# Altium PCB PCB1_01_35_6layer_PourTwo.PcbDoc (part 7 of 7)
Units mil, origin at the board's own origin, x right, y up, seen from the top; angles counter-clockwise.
Board outline 1023.62 x 688.98 mil, 6 copper layers (Top Layer, Layer 1, Layer 2, Layer 3, Layer 4, Bottom Layer), stack 32.112 mil thick; 0 components, 1 nets, 8 pads, 81 vias.

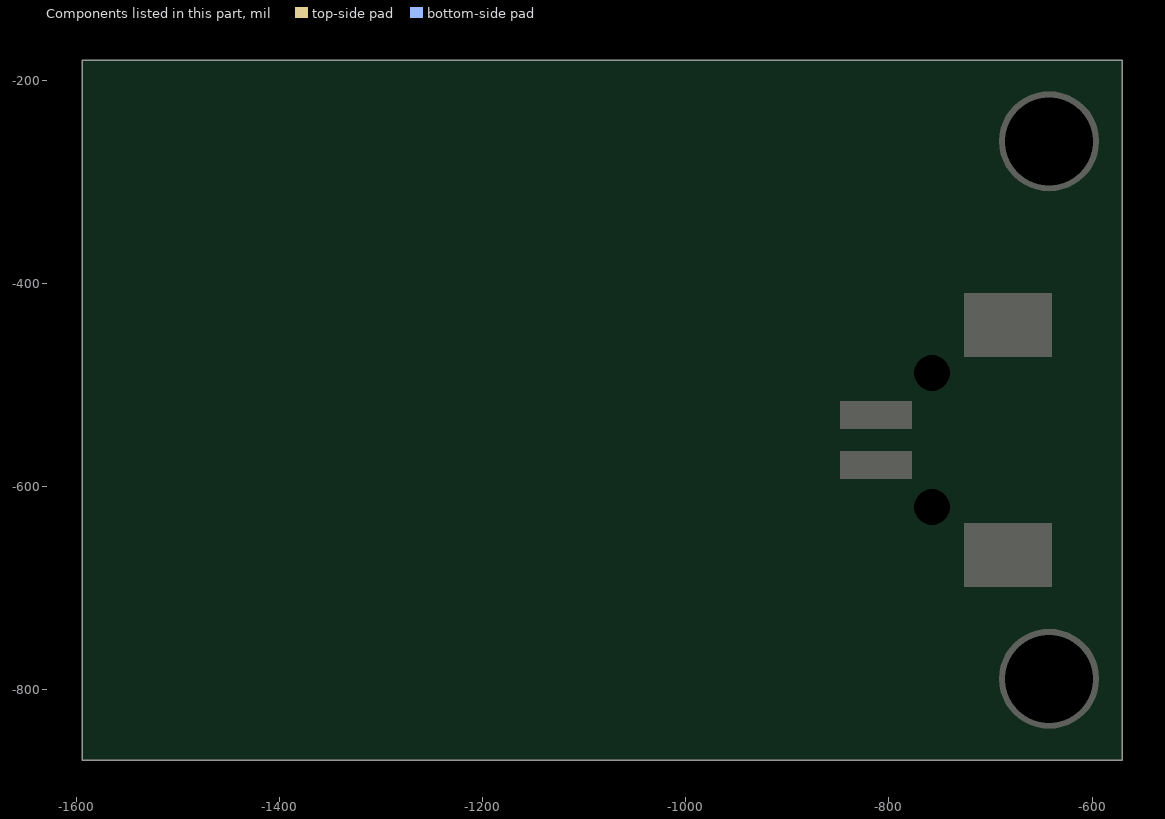
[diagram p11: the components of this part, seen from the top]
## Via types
v1: diameter 19.68, hole 11.81, Top Layer to Bottom Layer, tented both sides, 65 vias
v2: diameter 39.37, hole 19.68, Top Layer to Bottom Layer, 10 vias
v3: diameter 19.68, hole 11.81, Top Layer to Bottom Layer, 6 vias

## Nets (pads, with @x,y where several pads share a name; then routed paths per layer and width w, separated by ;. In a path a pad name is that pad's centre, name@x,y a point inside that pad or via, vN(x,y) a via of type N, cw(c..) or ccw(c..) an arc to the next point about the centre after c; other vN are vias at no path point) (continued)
copper on no net: (continued)
  Bottom Layer w3.94: -1461.98,-377.18 cw(c-1255.41,-519.9) -1425.28,-335.02 cw(c-1248.06,-527.67) -1380.34,-301.79 cw(c-1248.85,-525.96) -1329.45,-278.88 cw(c-1252.92,-513.07) -1274.85,-267.68 cw(c-1253.22,-516.36) -1219.21,-269.06 cw(c-1254.55,-527.16) -1165.21,-282.46 cw(c-1253.85,-525.77) -1115.33,-306.97 cw(c-1246.63,-514.62) -1072.08,-341.74 cw(c-1248.83,-515.94) -1037.83,-385.3 cw(c-1258.16,-521.9) -1013.84,-435.23 cw(c-1256.95,-521.66) -1001,-489.06 cw(c-1244,-520.15) -1000.21,-544.3 cw(c-1245.67,-519.37) -1011.89,-598.23 cw(c-1256.37,-515.91) -1034.98,-648.32 cw(c-1255.69,-516.53) -1068.13,-692.32 cw(c-1246.47,-525.36) -1110,-727.99 cw(c-1246.5,-524.21) -1158.78,-753.26 cw(c-1250.71,-513.6) -1211.86,-767.33 cw(c-1250.8,-514.2) -1266.66,-769.81 cw(c-1251.72,-526.67) -1320.59,-760.33 cw(c-1251.06,-526.64) -1370.93,-738.95 cw(c-1245.49,-516.49) -1415.41,-707.16 cw(c-1245.8,-516.56) -1452.09,-666.69 cw(c-1255.77,-523.64) -1479.04,-619.31 cw(c-1256.01,-524.43) -1494.6,-567.12 cw(c-1244.49,-522.22) -1498.42,-512.83 cw(c-1244.43,-522.04) -1490.65,-459.02 cw(c-1255.98,-518.94) -1471.41,-408.26 cw(c-1257.39,-518.91) -1441.26,-363.21 cw(c-1248.24,-526.48) -1402.03,-325.83 cw(c-1247.87,-526.66) -1355.82,-297.65 cw(c-1252.72,-516.03) -1304.68,-280.19 cw(c-1253.75,-514.2) -1250.98,-274.73 cw(c-1253.75,-526.23) -1197.42,-281.11 cw(c-1253.73,-526.92) -1146.48,-298.68 cw(c-1248.75,-516.66) -1100.64,-326.83 cw(c-1247.53,-514.14) -1062.37,-364.54 cw(c-1256.91,-521.89) -1033.28,-409.68 cw(c-1257.7,-522.48) -1014.44,-459.91 cw(c-1246.89,-519.85) -1006.93,-512.93 cw(c-1243.47,-519.18) -1011.57,-566.22 cw(c-1255.52,-516.87) -1027.74,-617.17 cw(c-1256.76,-516.51) -1054.32,-663.49 cw(c-1248.08,-523) -1090.23,-702.9 cw(c-1244.94,-525.75) -1134.04,-733.16 cw(c-1250.88,-514.89) -1183.38,-753.08 cw(c-1251.48,-513.42) -1235.78,-762.08 cw(c-1250.96,-523.97) -1288.79,-759.54 cw(c-1251.21,-528.8) -1339.81,-745.14 cw(c-1246.59,-517.21) -1386.39,-719.94 cw(c-1245.67,-515.57) -1426.53,-685.44 cw(c-1253.26,-522.5) -1458.23,-643.18 cw(c-1257.72,-525.7) -1479.56,-594.92 cw(c-1245.78,-521.86) -1489.78,-543.2 cw(c-1243.64,-521.5) -1488.79,-490.52 cw(c-1253.53,-520.1) -1476.48,-439.4 cw(c-1259.43,-518.46) -1453.01,-392.41 cw(c-1248.81,-525.24) -1419.82,-351.75 cw(c-1246.97,-526.87) -1378.78,-319.1 cw(c-1252.04,-518.6) -1331.76,-296.1 cw(c-1254.72,-512.42) -1280.83,-284.28 cw(c-1253.18,-524.96) -1228.6,-283.95 cw(c-1253.29,-527.7) -1177.51,-294.71 cw(c-1250.24,-518.79) -1130.04,-316.18 cw(c-1246.86,-512.3) -1088.65,-347.73 cw(c-1255.56,-521.49) -1055.26,-387.59 cw(c-1257.97,-523.3) -1031.12,-433.6 cw(c-1249.43,-520.09) -1017.46,-483.63 cw(c-1241.72,-518.49) -1015.39,-535.39 cw(c-1254.32,-517.64) -1024.78,-586.28 cw(c-1257.52,-516.86) -1044.75,-633.99 cw(c-1249.86,-521.25) -1074.45,-676.2 cw(c-1243.33,-526.56) -1112.84,-710.63 cw(c-1250.68,-516.32) -1157.82,-735.72 cw(c-1252.22,-513.11) -1207.09,-750.66 cw(c-1250.78,-521.53) -1258.31,-754.67 cw(c-1250.76,-530.44) -1309.06,-747.08 cw(c-1246.59,-515.82) -1399.55,-700.19 cw(c-1251.32,-521.1) -1435.12,-663.45 cw(c-1258.57,-527.06) -1461.51,-619.72 cw(c-1244.61,-520.96) -1482.93,-520.57 cw(c-1251.26,-520.66) -1477.32,-469.99 cw(c-1260.9,-518.75) -1460.54,-422 cw(c-1247.31,-525.64) -1398.09,-342.68 cw(c-1251.03,-520.65) -1355.74,-314.89 cw(c-1255.86,-511.62) -1308.3,-297.31 cw(c-1252.54,-526.47) -1207.86,-294.9 cw(c-1251.13,-520.85) -1159.68,-309.74 cw(c-1247.07,-511.04) -1116.1,-334.96 cw(c-1256.39,-523) -1050.54,-410.46 cw(c-1245.69,-518.31) -1023.05,-506.24 cw(c-1256.11,-517.94) -1039.36,-604.39 cw(c-1246.05,-523.06) -1095.37,-686.24 cw(c-1252.09,-515.05) -1180.98,-735.99 cw(c-1249.76,-525.69) -1279.27,-744.97 cw(c-1247.44,-516.34) -1371.71,-710.86 cw(c-1253.94,-524.56) -1440.95,-641.21 cw(c-1245.58,-520.66) -1473.43,-548.69 cw(c-1255.63,-520.82) -1463.95,-451.41 cw(c-1247.74,-524.7) -1413.6,-367.83 cw(c-1253.94,-517.34) -1333,-313.39 cw(c-1252.1,-525.51) -1236.98,-298.99 cw(c-1251.5,-522.7) -1188.99,-307.42 cw(c-1248.1,-511) -1144.12,-326.26 cw(c-1255.35,-522.69) -1072.19,-390.75 cw(c-1253.13,-521.62) -1048.21,-432.89 cw(c-1241.87,-516.76) -1034.19,-479.24 cw(c-1255.18,-518.53) -1038.02,-575.28 cw(c-1253.33,-519.47) -1055.12,-620.4 cw(c-1242.38,-525.07) -1081.75,-660.55 cw(c-1251.92,-516.16) -1157.82,-718.52 cw(c-1251.65,-517.82) -1203.26,-734.02 cw(c-1249,-529.85) -1250.93,-739.07 cw(c-1248.18,-517.21) -1343.62,-717.51 cw(c-1249.12,-518.12) -1384.31,-692.5 cw(c-1256.7,-527.8) -1418.43,-659.17 cw(c-1246.74,-520.67) -1460.67,-574.44 cw(c-1247.66,-520.41) -1467.3,-527.38 cw(c-1259.91,-520.74) -1463.39,-480.08 cw(c-1248.51,-523.81) -1425.22,-393.97 cw(c-1248.57,-523.16) -1393.34,-359.04 cw(c-1256.58,-513.97) -1354.61,-332.04 cw(c-1253.58,-520.23) -1310.87,-314.46 cw(c-1251.39,-527.55) -1264.39,-306.7 cw(c-1251.44,-524.25) -1217.4,-308.99 cw(c-1249.47,-512.32) -1172.14,-321.55 cw(c-1252.19,-518.09) -1130.93,-343.94 cw(c-1256.55,-524.58) -1095.51,-374.65 cw(c-1254.23,-522.64) -1067.47,-412.12 cw(c-1243.88,-516.61) -1048.39,-454.78 cw(c-1249.52,-518) -1039.41,-500.56 cw(c-1257.47,-518.79) -1040.5,-547.19 cw(c-1254.77,-519.3) -1051.45,-592.45 cw(c-1243.66,-523.4) -1072.05,-634.13 cw(c-1247.82,-520.23) -1101.45,-670.04 cw(c-1253.62,-514.49) -1137.88,-698.76 cw(c-1252.43,-516.66) -1179.52,-719.07 cw(c-1248.56,-527.69) -1224.52,-729.71 cw(c-1248.69,-523.06) -1270.69,-729.96 cw(c-1247.94,-514.77) -1315.81,-720.23 cw(c-1248.77,-516.8) -1357.77,-701.19 cw(c-1254.72,-526.67) -1394.48,-673.45 cw(c-1251.63,-524.07) -1423.94,-638.21 cw(c-1244.64,-519.28) -1445.09,-597.47 cw(c-1246.48,-519.84) -1457.09,-553.22 cw(c-1257.69,-521.51) -1459.11,-507.5 cw(c-1254.34,-522.21) -1450.79,-462.58 cw(c-1246.04,-524.6) -1432.96,-420.54 cw(c-1247.41,-523.66) -1406.65,-383.29 cw(c-1255.7,-516.21) -1372.9,-352.75 cw(c-1254.47,-518.75) -1333.19,-330.64 cw(c-1250.96,-526.8) -1289.66,-317.65 cw(c-1251.07,-525.42) -1244.43,-314.21 cw(c-1250.61,-514.48) -1199.62,-320.71 cw(c-1251.64,-516.45) -1157.5,-337.12 cw(c-1255.68,-524.4) -1119.95,-362.25 cw(c-1254.85,-523.64) -1088.64,-394.74 cw(c-1246.3,-517.16) -1065.21,-433.2 cw(c-1247.91,-517.35) -1051.08,-475.89 cw(c-1256.74,-519.34) -1046.54,-520.59 cw(c-1255.9,-519.49) -1051.59,-565.19 cw(c-1245.67,-521.89) -1066.2,-607.53 cw(c-1246.28,-521.04) -1089.96,-645.43 cw(c-1253.54,-515.41) -1121.35,-677.24 cw(c-1253.28,-515.96) -1158.73,-701.64 cw(c-1248.72,-525.18) -1200.44,-717.29 cw(c-1248.3,-524.75) -1244.54,-723.11 cw(c-1248.59,-515.45) -1288.82,-719.22 cw(c-1248.8,-515.75) -1331.22,-706.04 cw(c-1252.9,-524.92) -1369.66,-684 cw(c-1252.67,-525.47) -1402.08,-653.89 cw(c-1245.6,-519.24) -1427.16,-617.49 cw(c-1245.73,-519.15) -1443.93,-576.64 cw(c-1255.2,-521.77) -1451.41,-533.21 cw(c-1256.07,-522.32) -1448.91,-489.28 cw(c-1246.65,-523.83) -1436.9,-446.98 cw(c-1246.43,-523.76) -1416.22,-408.24 cw(c-1254.29,-518.27) -1387.69,-374.98 cw(c-1255.68,-517.5) -1352.44,-349.05 cw(c-1250.78,-525.81) -1312.42,-331.44 cw(c-1250.52,-526.18) -1269.62,-322.73 cw(c-1251.27,-516.86) -1226.04,-323.51 cw(c-1251.48,-514.72) -1183.83,-334.07 cw(c-1254.8,-523.88) -1144.97,-353.59 cw(c-1255.04,-524.53) -1111.17,-380.87 cw(c-1248.51,-518.17) -1084.14,-414.74 cw(c-1246.5,-516.35) -1065.47,-453.79 cw(c-1255.76,-519.66) -1055.8,-495.93 cw(c-1256.65,-519.91) -1055.28,-539.12 cw(c-1247.83,-520.87) -1064.11,-581.31 cw(c-1244.62,-521.45) -1082.19,-620.36 cw(c-1253.14,-516.39) -1108.35,-654.49 cw(c-1254.07,-515.69) -1141.12,-682.25 cw(c-1249.32,-522.91) -1179.03,-702.23 cw(c-1247.54,-526.26) -1220.42,-713.14 cw(c-1249.07,-516.41) -1263.14,-714.72 cw(c-1249.11,-515.01) -1305.18,-707.2 cw(c-1251.58,-523.04) -1344.52,-690.82 cw(c-1253.31,-527) -1379.11,-666.03 cw(c-1246.65,-519.51) -1407.4,-634.29 cw(c-1245.41,-518.45) -1428.28,-597.31 cw(c-1252.95,-521.57) -1440.66,-556.79 cw(c-1257.61,-522.84) -1443.6,-514.57 cw(c-1247.56,-523.19) -1437.21,-472.79 cw(c-1245.73,-523.54) -1422.1,-433.36 cw(c-1252.73,-519.82) -1398.91,-398.19 cw(c-1257.04,-516.71) -1368.43,-369.18 cw(c-1250.9,-524.7) -1332.37,-347.6 cw(c-1249.9,-526.54) -1292.59,-334.19 cw(c-1251.45,-519.01) -1250.94,-329.67 cw(c-1251.77,-513.23) -1209.4,-334.62 cw(c-1254.02,-523.06) -1170.02,-348.58 cw(c-1254.9,-525.19) -1134.54,-370.57 cw(c-1250.23,-519.4) -1104.68,-399.6 cw(c-1245.62,-515.2) -1082.14,-434.56 cw(c-1254.61,-519.72) -1067.88,-473.58 cw(c-1257.03,-520.45) -1062.24,-514.69 cw(c-1249.84,-520.36) -1065.57,-555.97 cw(c-1243.24,-521.35) -1078.06,-595.39 cw(c-1252.42,-517.3) -1098.91,-631.03 cw(c-1254.7,-515.78) -1126.84,-661.4 cw(c-1250.21,-521.09) -1160.56,-685.01 cw(c-1246.59,-527.16) -1198.67,-700.43 cw(c-1249.3,-517.56) -1239.19,-707.04 cw(c-1249.59,-514.62) -1280.15,-704.88 cw(c-1250.78,-521.23) -1319.61,-694.01 cw(c-1253.32,-528.23) -1355.57,-674.59 cw(c-1246.25,-518.44) -1410.6,-615 cw(c-1251.09,-521.03) -1427.27,-577.88 cw(c-1258.45,-523.61) -1435.2,-538.04 cw(c-1246.41,-522.84) -1424.41,-458.13 cw(c-1251.15,-520.87) -1406.55,-421.84 cw(c-1258.1,-516.65) -1381.05,-390.52 cw(c-1249.86,-525.43) -1313,-348.16 cw(c-1251.23,-520.85) -1273.89,-338.85 cw(c-1252.42,-512.5) -1233.75,-338.53 cw(c-1253.95,-524.39) -1158.2,-363.81 cw(c-1248.42,-516.68) -1100.6,-418.41 cw(c-1255.67,-520.64) -1072.11,-492.29 cw(c-1246.52,-520.05) -1077.42,-570.99 ; -1461.97,-377.18 ccw(c-1258.39,-517.16) -1488.26,-426.6 ccw(c-1245.64,-522.33) -1503.11,-480.66 ccw(c-1243.5,-522.86) -1506.15,-536.7 ccw(c-1253.98,-523.57) -1497.02,-592.09 ccw(c-1258.7,-524.33) -1475.61,-644.07 ccw(c-1246.41,-517.7) -1443.28,-690.16 ccw(c-1244.38,-516.17) -1401.86,-728.39 ccw(c-1250.39,-524.53) -1353.15,-756.79 ccw(c-1253.09,-529.34) -1299.22,-773.5 ccw(c-1250.33,-515.45) -1242.86,-777.99 ccw(c-1250.23,-512.58) -1186.76,-770.39 ccw(c-1247.66,-522.34) -1133.6,-750.88 ccw(c-1245.32,-528.12) -1086.14,-719.86 ccw(c-1254.39,-517.01) -1046.6,-679.11 ccw(c-1256.8,-514.9) -1016.57,-630.84 ccw(c-1247.84,-519.05) -997.64,-577.21 ccw(c-1241.19,-521.06) -991.25,-520.63 ccw(c-1255.68,-520.97) -997.48,-463.95 ccw(c-1259.18,-521.55) -1015.62,-409.81 ccw(c-1250.47,-517.38) -1045,-360.84 ccw(c-1244.14,-513.1) -1084.68,-319.67 ccw(c-1253.53,-524.32) -1132.52,-288.21 ccw(c-1255.47,-527.68) -1186.03,-267.6 ccw(c-1253.19,-518.53) -1242.73,-258.98 ccw(c-1252.46,-510.24) -1299.99,-263.33 ccw(c-1249.77,-524.73) -1354.95,-280.21 ccw(c-1248.28,-528.68) -1405.15,-308.43 ccw(c-1253.75,-521.28) -1448.11,-346.78 ccw(c-1260.18,-515.02) -1481.41,-393.87 ccw(c-1247.23,-522.21) -1503.52,-447.2 ccw(c-1246.64,-523) -1511.63,-561.9 ccw(c-1261.41,-524.29) -1496.53,-617.8 ccw(c-1247.57,-518.86) -1469.41,-669.05 ccw(c-1246.19,-518.63) -1385.85,-748.74 ccw(c-1254.84,-531.29) -1332.93,-772.84 ccw(c-1250.21,-517.14) -1275.92,-784.66 ccw(c-1249.48,-515.45) -1160.78,-771 ccw(c-1245.04,-530.62) -1108.25,-745.49 ccw(c-1252.99,-518.05) -1062.62,-708.94 ccw(c-1254.18,-516.08) -999.5,-611.11 ccw(c-1239.23,-522.43) -985.6,-554.14 ccw(c-1253.93,-520.57) -984.68,-495.45 ccw(c-1256.7,-520.3) -1019.99,-383.99 ccw(c-1241.94,-512.59) -1055.15,-336.77 ccw(c-1252.67,-522.68) -1099.98,-298.5 ccw(c-1254.91,-525.05) -1208.81,-254.49 ccw(c-1251.79,-515.44) -1326.15,-261.64 ccw(c-1249.92,-526.67) -1429.86,-317.69 ccw(c-1255.73,-517.79) -1499.43,-413.04 ccw(c-1245.41,-523.7) -1522.43,-529.15 ccw(c-1256.47,-522.59) -1493.19,-644 ccw(c-1244.89,-518.16) -1418.07,-736.1 ccw(c-1253.04,-526.42) -1310.52,-786.99 ccw(c-1248.98,-514.18) -1191.19,-787.81 ccw(c-1247.64,-526.19) -1082.98,-737.18 ccw(c-1254.8,-514.9) -1005.99,-645.38 ccw(c-1244.24,-521.67) -975.89,-529.27 ccw(c-1257.97,-519.99) -997.65,-410.96 ccw(c-1245.62,-515.92) -1068.2,-313.37 ccw(c-1255.95,-525.79) -1173.66,-254.5 ccw(c-1250.27,-508.3) -1233.51,-243.72 ccw(c-1250.8,-520.69) -1294.31,-246.61 ccw(c-1250.04,-527.91) -1407.33,-290.53 ccw(c-1259.95,-512.38) -1453.98,-329.92 ccw(c-1251.07,-520.33) -1490.65,-378.8 ccw(c-1244.57,-524.59) -1528.99,-494.35 ccw(c-1262.84,-522.36) -1528.38,-555.64 ccw(c-1251.59,-520.61) -1514.04,-615.28 ccw(c-1243.69,-518.13) -1449.18,-718.88 ccw(c-1257.01,-530.77) -1401.39,-757.64 ccw(c-1251.52,-521.45) -1346.07,-784.71 ccw(c-1247.93,-512.02) -1286.12,-799.31 ccw(c-1248.31,-516.41) -1224.42,-800.82 ccw(c-1246.96,-531.52) -1163.85,-788.66 ccw(c-1250.49,-521.94) -1107.51,-763.2 ccw(c-1255.65,-512.86) -1057.87,-726.16 ccw(c-1252.73,-515.72) -1017.22,-679.39 ccw(c-1240.19,-524.32) -987.85,-624.77 ccw(c-1249.24,-521.2) -971.5,-564.9 ccw(c-1259.86,-519.34) -968.39,-502.79 ccw(c-1256.13,-518.93) -978.56,-441.42 ccw(c-1241.5,-514.74) -1002.01,-383.75 ccw(c-1249.07,-519.44) -1037.85,-332.79 ccw(c-1257.52,-526.66) -1083.91,-290.65 ccw(c-1255.66,-523.79) -1137.89,-259.25 ccw(c-1249.58,-509.86) -1197.5,-240.47 ccw(c-1250.62,-518) -1259.86,-235.59 ccw(c-1250.43,-529.45) -1321.92,-244.26 ccw(c-1251.37,-526.53) -1380.75,-265.93 ccw(c-1258.22,-513.01) -1433.42,-300.01 ccw(c-1253.04,-518.41) -1477.11,-345.12 ccw(c-1243.84,-525.77) -1510.1,-398.67 ccw(c-1246.38,-524.78) -1530.98,-458.05 ccw(c-1261.1,-521.46) -1538.33,-520.6 ccw(c-1254.39,-520.88) -1531.4,-583.25 ccw(c-1242.53,-518.4) -1511.08,-643.03 ccw(c-1244.6,-519.59) -1478.51,-697.17 ccw(c-1256.45,-528.76) -1434.84,-742.89 ccw(c-1253.15,-523.81) -1381.94,-777.62 ccw(c-1247.35,-512.79) -1322.7,-800.14 ccw(c-1247.66,-514.8) -1259.98,-809.59 ccw(c-1248.14,-529.67) -1196.68,-805.07 ccw(c-1249.73,-524.76) -1135.97,-786.38 ccw(c-1254.66,-512.96) -1080.65,-754.96 ccw(c-1253.51,-514.2) -1033.21,-712.49 ccw(c-1242.46,-523.95) -996.2,-660.65 ccw(c-1246.55,-522.47) -971.8,-601.74 ccw(c-1259.09,-518.66) -960.71,-538.84 ccw(c-1257.77,-518.54) -963.22,-474.98 ccw(c-1243.35,-516.26) -979.63,-413.18 ccw(c-1246.31,-518.17) -1009.57,-356.62 ccw(c-1257.51,-525.59) -1051.13,-307.8 ccw(c-1257.01,-524.76) -1102.14,-268.89 ccw(c-1249.67,-512.33) -1160.43,-242.02 ccw(c-1249.79,-515.02) -1223.34,-228.99 ccw(c-1251.24,-528.7) -1287.68,-229.91 ccw(c-1251.52,-528.15) -1350.41,-244.47 ccw(c-1256.36,-514.74) -1408.48,-272.35 ccw(c-1254.82,-515.81) -1458.82,-312.66 ccw(c-1244.97,-525.87) -1499.27,-363.02 ccw(c-1245.27,-525.93) -1528.14,-420.86 ccw(c-1258.51,-521.18) -1543.73,-483.61 ccw(c-1257.58,-520.56) -1544.77,-548.33 ccw(c-1243.24,-519.35) -1531.7,-611.83 ccw(c-1243.02,-519.5) -1505.43,-671.16 ccw(c-1254.95,-526.58) -1466.88,-723.38 ccw(c-1255.49,-526.07) -1417.49,-765.59 ccw(c-1247.11,-513.99) -1360.01,-796.1 ccw(c-1246.72,-513.58) -1297.32,-813.73 ccw(c-1248.83,-527.08) -1232.27,-817.34 ccw(c-1249.51,-528.07) -1168.02,-806.16 ccw(c-1253.56,-513.62) -1107.66,-781.22 ccw(c-1253.81,-512.71) -1053.92,-744 ccw(c-1244.88,-522.78) -1009.51,-696.01 ccw(c-1243.83,-524.46) -977.05,-639.17 ccw(c-1257.83,-518.26) -957.72,-576.53 ccw(c-1259.06,-517.8) -952.13,-511.16 ccw(c-1245.82,-517.34) -960.83,-446.11 ccw(c-1242.99,-517.38) -984,-384.63 ccw(c-1256.95,-524.34) -1020.09,-329.62 ccw(c-1258.38,-525.24) -1067.08,-283.47 ccw(c-1250.44,-514.92) -1122.94,-248.58 ccw(c-1248.24,-511.94) -1185.31,-227.17 ccw(c-1251.83,-527.41) -1250.94,-219.89 ccw(c-1252.05,-529.47) -1316.69,-226.71 ccw(c-1254.89,-517.01) -1379.41,-247.59 ccw(c-1256.18,-512.61) -1435.88,-282.11 ccw(c-1246.38,-525.44) -1483.49,-328.21 ccw(c-1244.64,-527.18) -1520.27,-383.43 ccw(c-1255.85,-521.53) -1544.26,-445.29 ccw(c-1260.91,-519.52) -1553.69,-511.05 ccw(c-1244.54,-520.15) -1548.49,-577.35 ccw(c-1241.7,-519.84) -1529.31,-641.12 ccw(c-1252.97,-524.79) -1496.82,-699.25 ccw(c-1258.44,-527.94) -1452.02,-748.62 ccw(c-1247.37,-515.55) -1397.41,-787.01 ccw(c-1245.61,-512.83) -1335.83,-812.96 ccw(c-1248.9,-524.42) -1270.09,-825.02 ccw(c-1249.99,-531.51) -1203.25,-821.97 ccw(c-1252.52,-514.87) -1138.63,-804.3 ccw(c-1253.65,-511.42) -1079.17,-773.26 ccw(c-1246.95,-521.13) -1027.78,-730.15 ccw(c-1241.55,-527.04) -987.37,-676.52 ccw(c-1256.14,-518.3) -959.71,-615.24 ccw(c-1259.89,-516.84) -945.68,-549.4 ccw(c-1248.41,-517.84) -946.15,-482.09 ccw(c-1239.6,-517.32) -961.76,-416.53 ccw(c-1255.77,-523.05) -991.45,-355.94 ccw(c-1259.62,-525.23) -1033.39,-302.98 ccw(c-1251.73,-517.21) -1085.75,-260.27 ccw(c-1246.11,-509.39) -1146.42,-230.39 ccw(c-1252.04,-525.62) -1212.27,-214.6 ccw(c-1252.87,-530.37) -1280.06,-213.17 ccw(c-1254,-519.46) -1346.57,-226.33 ccw(c-1256.71,-509.41) -1408.49,-254.13 ccw(c-1247.92,-524.4) -1462.82,-294.95 ccw(c-1247.95,-525.39) -1539.65,-406.3 ccw(c-1263.6,-517.87) -1557.79,-471.97 ccw(c-1246.39,-520.65) -1560.97,-540.09 ccw(c-1245.08,-521.25) -1524,-670.73 ccw(c-1261.35,-528.85) -1484.84,-726.76 ccw(c-1248.23,-517.33) -1434.2,-772.79 ccw(c-1246.61,-516.24) -1309.52,-827.77 ccw(c-1251.18,-534.17) -1241.15,-833.34 ccw(c-1251.71,-516.74) -1173.16,-823.62 ccw(c-1251.68,-514.25) -1050.9,-762.38 ccw(c-1241.74,-528.11) -1002.82,-713.09 ccw(c-1251.51,-520.39) -967.16,-655.02 -960.96,-648.82 -935.18,-648.82 v2(-906,-678) ; v3(-1265,-541) -1265,-545.26 -1271.53,-551.79 -1271.53,-554.48 -1271.53,-559.53 -1271.53,-560.05 ccw(c-1249.17,-521.33) -1264.76,-563.23 ccw(c-1250.22,-524.17) -1255.19,-565.55 ccw(c-1250.21,-522.96) -1245.29,-565.56 ccw(c-1250.63,-519.14) -1235.55,-563.37 ccw(c-1251.26,-517.19) -1226.42,-559.16 ccw(c-1250.89,-517.74) -1218.31,-553.14 ccw(c-1249.02,-519.74) -1211.67,-545.5 ccw(c-1247.79,-520.79) -1204.4,-526.5 ccw(c-1253.15,-519.82) -1204.08,-516.16 ccw(c-1253.91,-519.78) -1209.84,-496.23 ccw(c-1250.34,-517.95) -1215.82,-487.61 ccw(c-1249,-516.88) -1223.72,-480.57 ccw(c-1251.35,-520.25) -1233.06,-475.49 ccw(c-1252.59,-523.19) -1243.35,-472.49 ccw(c-1252.72,-523.7) -1254.09,-471.66 ccw(c-1252.81,-521.51) -1264.79,-473.1 ccw(c-1253.63,-518.22) -1274.95,-476.92 ccw(c-1253.36,-518.41) -1284,-483.07 ccw(c-1250.56,-521.67) -1291.49,-491.13 ccw(c-1248.5,-523.26) -1297.17,-500.64 ccw(c-1248.84,-523.14) -1300.79,-511.16 ccw(c-1251.61,-522.53) -1302.09,-522.23 ccw(c-1255.01,-522.51) -1300.81,-533.4 ccw(c-1252.6,-521.82) -1296.94,-544 ccw(c-1248.9,-520) -1290.81,-553.58 ccw(c-1247.74,-519.18) -1273.21,-568.06 ccw(c-1249.71,-522.84) -1262.46,-572.18 ccw(c-1250.43,-525.41) -1250.96,-573.7 ccw(c-1250.41,-521.26) -1239.36,-572.53 ccw(c-1251.16,-517.59) -1228.21,-568.88 ccw(c-1251.53,-516.67) -1217.99,-562.98 ccw(c-1250.27,-518.34) -1209.2,-555.06 ccw(c-1247.5,-520.8) -1202.36,-545.35 ccw(c-1246.87,-521.31) -1197.96,-534.23 ccw(c-1251.42,-520.09) -1196.17,-522.34 ccw(c-1254.6,-519.92) -1196.92,-510.26 ccw(c-1254.64,-519.88) -1200.15,-498.54 ccw(c-1251.99,-518.81) -1205.8,-487.75 ccw(c-1248.78,-516.65) -1213.79,-478.46 ccw(c-1249.79,-517.97) -1223.79,-471.27 ccw(c-1252.07,-522.02) -1235.19,-466.43 ccw(c-1252.81,-524.33) -1247.44,-464.05 ccw(c-1252.77,-523.39) -1259.94,-464.24 ccw(c-1253.22,-519.91) -1272.14,-467.12 ccw(c-1253.67,-518.03) -1293.13,-480.94 ccw(c-1249.08,-522.78) -1300.89,-491.06 ccw(c-1248.51,-523.28) -1309.46,-515.13 ccw(c-1253.56,-522.51) -1309.68,-528.02 ccw(c-1255.53,-522.59) -1306.85,-540.7 ccw(c-1250.82,-520.94) -1301.19,-552.45 ccw(c-1247.59,-518.96) -1293.11,-562.8 ccw(c-1247.18,-518.64) -1283.04,-571.31 ccw(c-1248.73,-520.97) -1271.39,-577.52 ccw(c-1250.3,-524.92) -1258.57,-580.99 ccw(c-1250.4,-524.35) -1245.23,-581.34 ccw(c-1250.84,-519.23) -1232.09,-578.7 ccw(c-1251.71,-516.32) -1219.7,-573.35 ccw(c-1251.4,-516.78) -1208.64,-565.53 ccw(c-1249.02,-519.43) -1199.49,-555.53 ccw(c-1245.64,-521.9) -1192.83,-543.61 ccw(c-1248.64,-520.81) -1189.13,-530.43 ccw(c-1253.46,-519.99) -1188.37,-516.67 ccw(c-1254.99,-519.96) -1195.4,-489.98 ccw(c-1250.32,-517.69) -1203.04,-478.35 ccw(c-1247.87,-515.75) -1213.24,-468.74 ccw(c-1250.83,-519.8) -1225.42,-461.71 ccw(c-1252.63,-523.82) -1238.9,-457.42 ccw(c-1252.9,-524.85) -1253.05,-455.98 ccw(c-1252.95,-522.22) -1267.2,-457.53 ccw(c-1253.95,-517.77) -1280.7,-462.19 ccw(c-1254.11,-517.01) -1292.8,-469.95 ccw(c-1250.59,-521.33) -1302.89,-480.26 ccw(c-1247.72,-523.65) -1310.64,-492.55 ccw(c-1247.81,-523.66) -1315.71,-506.2 ccw(c-1251.25,-522.82) -1317.78,-520.64 ccw(c-1255.95,-522.67) -1316.52,-535.26 ccw(c-1253.85,-522.05) -1311.85,-549.22 ccw(c-1248.91,-519.77) -1304.19,-561.88 ccw(c-1246.67,-518.13) -1294,-572.74 ccw(c-1247.45,-519.1) -1281.77,-581.28 ccw(c-1249.49,-522.87) -1267.97,-586.99 ccw(c-1250.36,-524.87) -1238.08,-588.26 ccw(c-1251.45,-517.2) -1223.54,-583.91 ccw(c-1251.58,-516.49) -1198.56,-566.69 ccw(c-1247.14,-520.85) -1189.4,-554.43 ccw(c-1245.36,-522.05) -1183.33,-540.27 ccw(c-1250.98,-520.39) -1180.63,-525.06 ccw(c-1255.33,-520.06) -1181.2,-509.53 ccw(c-1255.82,-520.07) -1184.97,-494.39 ccw(c-1252.62,-518.86) -1191.84,-480.37 ccw(c-1248.31,-516.12) -1201.73,-468.19 ccw(c-1248.77,-516.91) -1214.26,-458.65 ccw(c-1251.83,-522.02) -1228.65,-452.08 ccw(c-1252.97,-525.28) -1244.19,-448.65 ccw(c-1252.94,-524.5) -1260.14,-448.49 ccw(c-1253.39,-520.22) -1275.77,-451.74 ccw(c-1254.91,-515.52) -1290.33,-458.52 ccw(c-1252.72,-518.79) -1302.94,-468.54 ccw(c-1248.76,-522.81) -1313.13,-481.13 ccw(c-1247.5,-523.79) -1324.78,-511.35 ccw(c-1253.66,-522.7) -1325.51,-527.66 ccw(c-1257.17,-522.85) -1322.4,-543.79 ccw(c-1251.56,-521.03) -1315.66,-558.81 ccw(c-1247.19,-518.51) -1305.81,-572.14 ccw(c-1246.33,-517.8) -1293.38,-583.19 ccw(c-1248.16,-520.43) -1278.91,-591.41 ccw(c-1250.3,-525.41) -1262.92,-596.23 ccw(c-1250.62,-525.99) -1246.17,-597.16 ccw(c-1251,-519.58) -1229.57,-594.3 ccw(c-1252.1,-515.55) -1213.86,-587.98 ccw(c-1251.94,-515.72) -1199.74,-578.55 ccw(c-1249.2,-518.95) -1187.93,-566.32 ; -1187.93,-566.33 ccw(c-1244.82,-522.33) -1179.16,-551.67 ccw(c-1247.44,-521.38) -1174.06,-535.32 ccw(c-1253.55,-520.18) -1172.65,-518.16 ccw(c-1256.12,-520.13) -1180.55,-484.63 ccw(c-1250.54,-517.58) -1189.65,-469.87 ccw(c-1248.49,-516.42) -1216.89,-448.37 ccw(c-1252.63,-524.27) -1233.51,-442.59 ccw(c-1252.95,-524.83) -1268.64,-441.79 ccw(c-1254.18,-517.58) -1285.54,-447.08 ccw(c-1254.1,-517.14) -1300.85,-456.22 ccw(c-1250.49,-521.91) -1313.8,-468.59 ccw(c-1248.8,-523.49) -1330.62,-500.18 ccw(c-1254.52,-521.78) -1333.54,-518 ccw(c-1254.15,-521.56) -1332.28,-536.09 ccw(c-1248.64,-520.58) -1327.06,-553.54 ccw(c-1247.71,-520.38) -1306.25,-583.38 ccw(c-1252.4,-525.23) -1291.42,-594.21 ccw(c-1251.16,-522.66) -1274.44,-601.39 ccw(c-1249.66,-517.76) -1256.23,-604.74 ccw(c-1249.52,-516.76) -1237.66,-604.19 ccw(c-1249.01,-520.14) -1219.61,-599.69 ccw(c-1248.22,-523.02) -1188.65,-579.13 ccw(c-1253.3,-517.68) -1177.19,-564.2 ccw(c-1253.27,-517.62) -1169.09,-547.15 ccw(c-1249.29,-518.96) -1164.85,-528.73 ccw(c-1245.56,-519.5) -1164.91,-509.75 ccw(c-1251.54,-520.22) -1169.25,-491.2 ccw(c-1255.07,-521.4) -1177.45,-473.93 ccw(c-1254.24,-520.82) -1189.13,-458.73 ccw(c-1250.75,-517.43) -1203.86,-446.41 ccw(c-1249.68,-516.2) -1221.1,-437.76 ccw(c-1251.85,-522.04) -1239.88,-433.12 ccw(c-1252.27,-524.11) -1278.44,-436.09 ccw(c-1254.09,-517.66) -1296.38,-443.78 ccw(c-1253.36,-518.43) -1312.12,-455.42 ccw(c-1249.38,-522.77) -1324.99,-470.27 ccw(c-1248.99,-523.28) -1340.12,-506.5 ccw(c-1256.24,-521.79) -1341.38,-526.29 ccw(c-1252.63,-521.42) -1338.08,-545.89 ccw(c-1247.5,-520) -1330.59,-564.4 ccw(c-1246.74,-519.68) -1319.36,-580.97 ccw(c-1249.69,-522.24) -1304.83,-594.79 ccw(c-1251.59,-524.2) -1268.22,-611.04 ccw(c-1249.69,-516.65) -1248.02,-612.82 ccw(c-1249.62,-516.92) -1227.86,-610.33 ccw(c-1248.5,-521.5) -1208.67,-603.54 ccw(c-1247.06,-524.78) -1191.47,-592.51 ccw(c-1251.22,-519.7) -1177.14,-577.87 ccw(c-1254.13,-517.32) -1166.19,-560.45 ccw(c-1252.87,-517.86) -1159.13,-541.08 ccw(c-1247.63,-519.12) -1156.46,-520.6 ccw(c-1246.55,-519.38) -1158.56,-499.97 ccw(c-1252.99,-520.76) -1165.19,-480.26 ccw(c-1254.75,-521.38) -1190.1,-447 ccw(c-1249.79,-515.85) -1207.42,-435.18 ccw(c-1250.39,-517.55) -1227.05,-427.63 ccw(c-1251.98,-523.48) -1247.92,-424.53 ccw(c-1252.12,-525.2) -1269.06,-425.87 ccw(c-1252.77,-521.79) -1289.45,-431.68 ccw(c-1255.05,-516.2) -1308.09,-441.94 ccw(c-1252.33,-519.73) -1323.93,-456.22 ccw(c-1248.26,-523.43) -1336.38,-473.64 ccw(c-1247.78,-523.78) -1344.92,-493.34 ccw(c-1252.01,-522.52) -1349.06,-514.44 ccw(c-1254.33,-521.92) -1342.69,-556.9 ccw(c-1246.58,-519.37) -1332.7,-576.19 ccw(c-1247.03,-519.76) -1318.86,-592.99 ccw(c-1250.65,-523.53) -1301.7,-606.43 ccw(c-1252.52,-526.22) -1281.84,-615.62 ccw(c-1250.3,-519.52) -1260.37,-620.16 ccw(c-1249.85,-515.79) -1238.35,-620.05 ccw(c-1249.59,-517.52) -1216.8,-615.32 ccw(c-1247.67,-523.12) -1196.77,-605.96 ccw(c-1247.66,-523.66) -1179.37,-592.21 ccw(c-1252.51,-518.72) -1165.37,-574.91 ccw(c-1253.71,-517.72) -1149.64,-533.36 ccw(c-1245.65,-519.07) -1148.92,-510.96 ccw(c-1248.23,-519.55) -1153.37,-488.93 ccw(c-1254.32,-521.45) -1162.54,-468.31 ccw(c-1255.68,-522.15) -1175.86,-450.02 ccw(c-1252.79,-519.45) -1192.78,-434.97 ccw(c-1249.1,-514.27) -1212.71,-424.06 ccw(c-1250.96,-519.24) -1234.66,-417.97 ccw(c-1251.92,-524.8) -1257.49,-416.72 ccw(c-1251.99,-525.12) -1280.13,-420.3 ccw(c-1253.32,-520.37) -1301.5,-428.65 ccw(c-1255.67,-515.72) -1320.49,-441.69 ccw(c-1251.03,-520.98) -1336.08,-458.71 ccw(c-1247.24,-523.85) -1347.74,-478.74 ccw(c-1248.12,-523.54) -1354.96,-500.81 ccw(c-1253.78,-522.39) -1357.22,-523.94 ccw(c-1256.61,-522.21) -1354.12,-547.06 ccw(c-1249.33,-520.39) -1345.93,-568.98 ccw(c-1246.6,-519.19) -1316.68,-605.41 ccw(c-1251.66,-525.25) -1296.81,-618.06 ccw(c-1251.81,-524.86) -1274.5,-625.84 ccw(c-1250.17,-517.85) -1250.95,-628.54 ccw(c-1249.94,-516.66) -1204.62,-618.96 ccw(c-1246.5,-524.86) -1184.09,-606.8 ccw(c-1248.82,-522.22) -1166.84,-590.21 ccw(c-1253.84,-517.97) -1153.55,-570.22 ccw(c-1254.96,-517.29) -1144.72,-547.82 ccw(c-1250.63,-518.42) -1140.86,-524.04 ccw(c-1246.58,-518.94) -1149.51,-476.74 ccw(c-1255.4,-522.22) -1161.42,-455.53 ccw(c-1255.45,-522.15) -1177.53,-437.25 ccw(c-1251.79,-518.08) -1197.21,-422.84 ccw(c-1249.18,-513.78) -1219.74,-413.26 ccw(c-1251.32,-521.11) -1243.89,-408.98 ccw(c-1251.72,-525.86) -1268.5,-409.93 ccw(c-1251.99,-524.57) -1292.4,-416.02 ccw(c-1254.25,-518.66) -1314.43,-427.18 ccw(c-1255.27,-516.62) -1333.38,-443.15 ccw(c-1249.54,-522.07) -1348.36,-462.97 ccw(c-1247.33,-523.61) -1364.36,-509.92 ccw(c-1255.94,-522.48) -1364.37,-534.93 ccw(c-1254.85,-522.03) -1358.63,-559.33 ccw(c-1247.81,-519.56) -1347.65,-581.96 ccw(c-1247.02,-519.37) -1312.72,-618 ccw(c-1252.5,-527.23) -1290.14,-629.45 ccw(c-1251.18,-522.98) -1265.49,-635.45 ccw(c-1250.26,-516.3) -1240.03,-635.98 ccw(c-1250.26,-515.25) -1214.96,-631.16 ccw(c-1248.74,-520.03) -1191.49,-621.09 ccw(c-1247.27,-523.43) -1154.11,-586.44 ccw(c-1255.07,-517.48) -1141.9,-563.75 ccw(c-1254.71,-517.53) -1134.7,-538.96 ccw(c-1248.77,-518.53) -1133.01,-513.17 ccw(c-1244.04,-518.49) -1137.26,-487.6 ccw(c-1251.94,-520.75) -1147.15,-463.57 ccw(c-1256.14,-522.95) -1161.96,-442.11 ccw(c-1254.88,-521.75) -1180.97,-424.21 ccw(c-1250.77,-516.23) -1203.46,-410.87 ccw(c-1249.84,-514.93) -1228.48,-403.02 ccw(c-1251.44,-523.02) -1254.69,-400.89 ccw(c-1251.59,-525.37) -1305.7,-413.22 ccw(c-1255.57,-516.77) -1328.03,-427.41 ccw(c-1254.02,-518.16) -1346.55,-446.39 ccw(c-1247.99,-522.92) -1360.54,-469.02 ccw(c-1246.08,-523.94) -1369.49,-494.16 ccw(c-1250.36,-522.99) -1372.9,-520.63 ccw(c-1258.07,-522.85) -1370.3,-547.27 ccw(c-1252.81,-521.5) -1361.67,-572.66 ccw(c-1246.55,-518.64) -1347.72,-595.68 ccw(c-1245.91,-518.27) -1329.22,-615.31 ccw(c-1249.48,-522.54) -1306.94,-630.54 ccw(c-1251.41,-525.13) -1254.86,-644.22 ccw(c-1250.52,-515.02) -1227.71,-642.26 ccw(c-1250.3,-515.72) -1201.53,-634.65 ccw(c-1247.74,-521.8) -1177.59,-621.55 ccw(c-1245.46,-525.42) -1157.22,-603.27 ccw(c-1251.99,-519.63) -1141.4,-580.85 ccw(c-1256.04,-517.28) -1130.65,-555.51 ccw(c-1253.92,-517.83) -1125.46,-528.44 ccw(c-1246.49,-518.39) -1126.32,-500.86 ccw(c-1245.68,-518.62) -1133.5,-474.14 ccw(c-1253.66,-521.72) -1146.42,-449.59 ccw(c-1255.4,-522.6) -1186.25,-411.13 ccw(c-1249.84,-513.97) -1211.52,-399.29 ccw(c-1250.5,-516.97) -1238.89,-393.55 ccw(c-1251.31,-524.81) -1266.95,-393.89 ccw(c-1251.18,-526.72) -1294.38,-400.12 ccw(c-1252.85,-522.08) -1319.86,-412.05 ccw(c-1257.02,-515.24) -1342.09,-429.44 ccw(c-1252.38,-519.67) -1359.79,-451.47 ccw(c-1246.53,-523.48) -1372.4,-476.89 ccw(c-1246.19,-523.71) -1379.41,-504.43 ccw(c-1252.28,-522.9) -1380.36,-532.85 ccw(c-1258.88,-523.31) -1374.82,-560.83 ccw(c-1250.75,-520.65) -1363.09,-586.88 ccw(c-1245.64,-517.74) -1346.02,-609.93 ccw(c-1246.42,-518.59) -1324.48,-628.91 ccw(c-1250.52,-524.49) -1299.31,-642.78 ccw(c-1252.17,-527.79) -1271.56,-650.55 ccw(c-1250.7,-518.73) -1242.7,-651.95 ccw(c-1250.73,-515.04) -1187.14,-636.55 ccw(c-1246.29,-523.78) -1163.12,-620.21 ccw(c-1246.68,-523.91) -1143.45,-598.74 ccw(c-1253.77,-518.68) -1128.93,-573.41 ccw(c-1255.02,-517.83) -1117.23,-516.36 ccw(c-1243.99,-517.92) -1120.99,-487.24 ccw(c-1247.91,-519.22) -1131.34,-459.71 ccw(c-1255.11,-522.81) -1147.46,-434.99 ccw(c-1256.43,-523.75) -1168.45,-414.15 ccw(c-1253.05,-519.41) -1193.4,-398.25 ccw(c-1249.4,-512.04) -1221.37,-388.36 ccw(c-1250.9,-519.29) -1250.9,-385.07 ccw(c-1250.99,-526.33) -1280.56,-388.2 ccw(c-1251.08,-526.37) -1308.95,-397.48 ccw(c-1253.91,-520.27) -1334.69,-412.66 ccw(c-1257.59,-515.11) -1356.37,-433.35 ccw(c-1250.47,-521) -1372.87,-458.44 ccw(c-1245.32,-523.73) -1383.7,-486.55 ccw(c-1246.89,-523.42) -1388.41,-516.34 ccw(c-1254.65,-523.1) -1386.52,-546.47 ccw(c-1257.63,-523.29) -1377.76,-575.44 ccw(c-1248.82,-519.53) -1362.76,-601.81 ccw(c-1246.01,-517.78) -1317.85,-642.4 ccw(c-1251.46,-526.93) -1289.84,-654.47 ccw(c-1251.5,-525.69) -1259.74,-659.81 ccw(c-1250.87,-516.67) -1229.13,-658.42 ccw(c-1250.71,-515.67) -1172,-636.7 ccw(c-1244.51,-525.66) -1148.33,-616.97 ccw(c-1248.49,-522.27) -1129.77,-592.31 ccw(c-1255.49,-518.05) -1116.94,-564.13 ccw(c-1256.68,-517.54) -1110.28,-533.83 ccw(c-1250.61,-518.13) -1110.24,-502.8 ccw(c-1245.88,-518.09) -1130.93,-444.48 ccw(c-1256.19,-523.9) -1150.36,-419.99 ccw(c-1255.99,-523.54) -1174.53,-400.07 ccw(c-1252.01,-517.38) -1202.43,-385.82 ccw(c-1249.74,-511.93) -1232.94,-378.29 ccw(c-1250.98,-521.7) -1264.41,-377.79 ccw(c-1250.55,-527.44) -1295.37,-383.99 ccw(c-1251.27,-525.48) -1324.37,-396.56 ccw(c-1255.46,-518.23) -1349.96,-415.16 ccw(c-1256.61,-516.43) -1370.65,-439.2 ccw(c-1248.43,-522.04) -1385.55,-467.28 ccw(c-1245.88,-523.33) -1396.24,-529.79 ccw(c-1257.37,-523.65) -1391.17,-561.34 ccw(c-1255.29,-522.65) -1378.97,-590.93 ccw(c-1247.17,-518.25) -1360.56,-617.23 ccw(c-1246.64,-518.25) -1309.3,-655.54 ccw(c-1252.06,-529.44) -1278.57,-665.36 ccw(c-1251.09,-523.16) -1246.36,-667.92 ccw(c-1251.27,-514.89) -1214.26,-663.45 ccw(c-1251.39,-513.98) -1183.74,-652.34 ccw(c-1248.36,-519.96) -1156.3,-634.97 ccw(c-1246.27,-523.51) -1116.41,-583.95 ccw(c-1256.96,-517.74) -1105.66,-553.05 ccw(c-1256.11,-517.83) -1101.62,-520.53 ccw(c-1248.16,-517.89) -1104.69,-487.9 ccw(c-1242.9,-517.06) -1115.17,-456.75 ccw(c-1252.31,-521.46) -1132.37,-428.67 ccw(c-1256.83,-524.82) -1155.2,-404.8 ccw(c-1255.23,-522.77) -1182.55,-386.24 ccw(c-1251.07,-514.81) -1213.33,-374.09 ccw(c-1250.38,-513.83) -1246.15,-369.32 ccw(c-1250.75,-524.02) -1279.29,-371.91 ccw(c-1250.6,-526.39) -1340.45,-397.49 ccw(c-1257.49,-516.15) -1365.43,-419.66 ccw(c-1254.65,-518.15) -1384.7,-447.01 ccw(c-1246.45,-522.74) -1397.59,-477.99 ccw(c-1244.26,-523.51) -1403.72,-511.05 ccw(c-1250.14,-523.15) -1402.69,-544.67 ccw(c-1259.72,-524.5) -1394.11,-577.27 ccw(c-1252.83,-521.56) -1378.32,-607.11 ccw(c-1245.9,-516.96) -1356.41,-632.93 ccw(c-1245.47,-516.67) -1329.53,-653.63 ccw(c-1249.22,-522.97) -1298.84,-668.09 ccw(c-1251.95,-530.54) -1265.58,-675.22 ccw(c-1251.04,-520.5) -1231.52,-674.67 ccw(c-1251.81,-513.54) -1198.25,-666.86 ccw(c-1251.26,-514.76) -1167.33,-652.23 ccw(c-1246.73,-522.04) -1140.29,-631.24 ccw(c-1243.75,-525.55) -1118.72,-604.56 ccw(c-1252.91,-519.7) -1103.6,-573.68 ccw(c-1256.99,-517.99) -1094.26,-505.73 ccw(c-1245.33,-517.25) -1100.8,-471.81 ccw(c-1245.15,-517.67) -1114.97,-440.24 ccw(c-1254.17,-522.94) -1135.79,-412.49 ccw(c-1255.71,-523.93) -1192.52,-372.91 ccw(c-1250.4,-511.89) -1226.03,-363.32 ccw(c-1250.79,-516.56) -1260.89,-361.66 ccw(c-1250.26,-526.08) -1295.39,-367.62 ccw(c-1249.84,-527.99) -1327.93,-380.7 ccw(c-1252.99,-522.28) -1356.95,-400.4 ccw(c-1259.37,-514.77) -1380.85,-426.2 ccw(c-1252.31,-519.69) -1398.28,-456.79 ccw(c-1244.7,-523.09) -1408.77,-490.51 ccw(c-1244.66,-523.22) -1411.98,-525.73 ccw(c-1252.63,-523.43) -1407.55,-560.83 ccw(c-1260.13,-525.06) -1395.22,-594.08 ccw(c-1250.49,-520.13) -1375.7,-623.75 ccw(c-1245.1,-515.81) -1350.24,-648.67 ccw(c-1246.15,-517.33) -1320.1,-667.72 ccw(c-1250.14,-525.63) -1286.52,-679.77 ccw(c-1250.81,-526.46) -1250.96,-683.88 ccw(c-1250.71,-517.2) -1215.3,-680.07 ccw(c-1250.98,-515.4) -1181.19,-668.76 ccw(c-1248.25,-521.16) -1150.3,-650.34 ccw(c-1246.29,-524.27) -1124.3,-625.4 ccw(c-1253.32,-518.34) -1104.36,-595.29 ccw(c-1255.08,-517.3) -1091.26,-561.57 ccw(c-1249.01,-518.83) -1085.72,-525.79 ccw(c-1244.89,-519.31) -1088.38,-489.61 ccw(c-1254.08,-520.97) -1098.95,-454.83 ccw(c-1256.2,-521.75) -1116.7,-423.03 ccw(c-1251.25,-518.12) -1140.9,-395.77 ccw(c-1247.96,-514.9) -1170.67,-374.62 ccw(c-1252.58,-523.14) -1204.43,-360.51 ccw(c-1253.4,-525.47) -1240.49,-353.88 ccw(c-1253.05,-519.48) -1277.15,-355.16 ccw(c-1253.53,-514.44) -1312.66,-364.67 ccw(c-1250.08,-523.35) -1345.27,-381.8 ccw(c-1248.68,-525.65) -1373.54,-405.52 ccw(c-1252.98,-521.65) -1396.07,-434.78 ccw(c-1257.55,-518.6) -1411.48,-468.42 ccw(c-1248.42,-521.64) -1419.11,-504.7 ccw(c-1247.96,-522.07) -1410.61,-578.09 ccw(c-1256.88,-524.54) -1394.42,-611.63 ccw(c-1248.67,-519.4) -1371.17,-640.82 ccw(c-1247.83,-519.09) -1308.79,-681.31 ccw(c-1251.71,-527.89) -1272.39,-690.27 ccw(c-1250.44,-518.24) -1234.85,-690.96 ccw(c-1250.18,-517.09) -1163.43,-668.56 ccw(c-1245.68,-525.96) -1133.12,-646.09 ccw(c-1252.32,-518.83) -1108.5,-617.41 ccw(c-1253.31,-517.72) -1080.07,-547.65 ccw(c-1243.29,-519.94) -1078.05,-509.74 ccw(c-1253.02,-520.52) -1084.49,-472.25 ccw(c-1254.8,-520.67) -1120.36,-405.46 ccw(c-1246.5,-514.14) -1148.46,-379.56 ccw(c-1252.22,-522) -1181.66,-360.52 ccw(c-1253.37,-523.77) -1256.46,-345.49 ccw(c-1253.14,-512.94) -1294.56,-350.66 ccw(c-1250.74,-522.3) -1330.62,-364.19 ccw(c-1249.94,-524.6) -1390.25,-412.56 ccw(c-1254.46,-519.8) -1423.33,-482.05 ccw(c-1247.08,-522.36) -1424.06,-559.31 ccw(c-1253.99,-522.9) -1391.4,-629.53 ccw(c-1247.04,-518.63) -1331.96,-679.64 ccw(c-1251.15,-524.63) -1256.58,-699.36 ccw(c-1250.01,-516.2) -1179.6,-685.41 ccw(c-1247.84,-523.49) -1115.97,-639.62 ccw(c-1253.86,-517.03) -1077.43,-570.99
  other v2: -879,-678 -898,-591 -897,-502 -877,-439

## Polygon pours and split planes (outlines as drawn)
Net1 on Top Layer "NET1_L01_P002" (solid, pour order 2): -1594.05,-194.94 -1594.31,-179.93 -570.69,-179.93 -570.69,-868.91 -1594.01,-868.91
Net1 on Bottom Layer "NET1_L06_P010" (solid, pour order 10): -1594.05,-194.94 -1594.31,-179.93 -570.69,-179.93 -570.69,-868.91 -1594.01,-868.91

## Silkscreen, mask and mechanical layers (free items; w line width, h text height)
Top Overlay:
  lines w7.87: -781.43,-648.49 -781.43,-665.22 -742.06,-665.22 ; -781.43,-459.51 -781.43,-442.78 -742.06,-442.78 ; -614.1,-665.22 -584.57,-665.22 -584.57,-442.78 -614.1,-442.78
  text "TYP-A 6-LAYER 35-COILS" at -987.89,-839 h23.62
Mechanical 2:
  the board outline again, w10
Mechanical 13:
  lines w3.94: -781.43,-665.22 -584.57,-665.22 -584.57,-442.78 -781.43,-442.78 -781.43,-665.22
